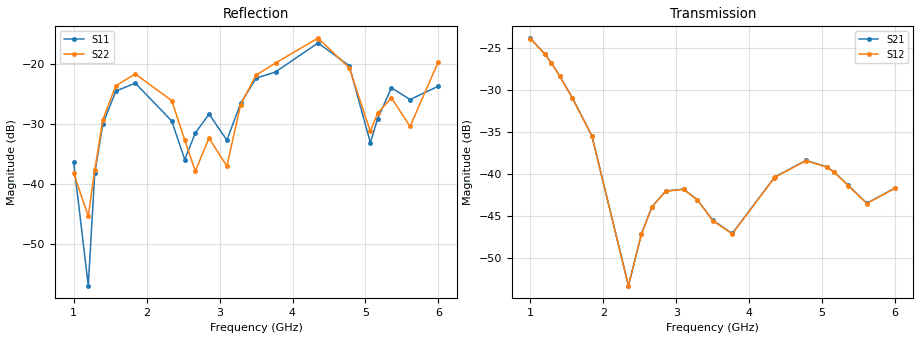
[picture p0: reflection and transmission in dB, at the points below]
!Agilent Technologies,E8364B,MY43040528,A.07.50.67
!Agilent E8364B: A.07.50.67
!Date: Sunday, March 01, 2026 16:25:24
!Correction: S11(Full 2 Port(1,2))
!S21(Full 2 Port(1,2))
!S12(Full 2 Port(1,2))
!S22(Full 2 Port(1,2))
!S2P File: Measurements: S11, S21, S12, S22:
# Hz S  dB  R 50
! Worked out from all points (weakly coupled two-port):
!   451 points, 1 GHz to 6 GHz, reference 50 ohm
!   highest |S21| = -23.84 dB at 1 GHz (marker M1); lowest = -53.3 dB at 2.344 GHz (marker M2)
!   lowest |S11| = -56.9 dB at 1.2 GHz (marker M3), VSWR 1.00, Z = 50 - j0.135 ohm
!   |S11| at or under -10 dB: start of sweep to end of sweep
!   |S22| runs from -45.5 to -15.6 dB; largest |S21 - S12| = 0.00028
!   S11 on the Smith chart (normalised r, x): 1 GHz: 1.03, +0.01; 4.356 GHz: 1.20, -0.26; 6 GHz: 0.97, -0.13
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1e9  -36.34 24.0  -23.84 153.1  -23.88 153.1  -38.19 -15.4
1.2e9  -56.87 -69.7  -25.70 38.8  -25.74 38.8  -45.28 77.3
1.288889e9  -38.14 -149.8  -26.76 -11.6  -26.79 -11.5  -37.62 117.9
1.4e9  -29.95 -177.1  -28.28 -73.5  -28.31 -73.4  -29.23 102.9
1.577778e9  -24.49 140.2  -30.95 -169.8  -30.98 -169.8  -23.59 57.6
1.844444e9  -23.16 87.5  -35.46 47.9  -35.49 48.0  -21.63 -7.6
2.344444e9  -29.46 26.8  -53.29 -150.0  -53.29 -150.1  -26.07 -107.4
2.522222e9  -35.88 46.6  -47.13 174.1  -47.18 174.3  -32.62 -134.1
2.666667e9  -31.49 76.9  -43.89 104.4  -43.91 104.4  -37.79 -93.9
2.855556e9  -28.30 54.5  -42.02 5.6  -42.05 5.7  -32.32 -97.6
3.1e9  -32.65 55.7  -41.79 -124.4  -41.83 -124.4  -36.97 -84.8
3.288889e9  -26.53 78.3  -43.05 137.5  -43.08 137.5  -26.74 -77.4
3.5e9  -22.34 50.8  -45.49 37.1  -45.54 37.2  -21.84 -120.5
3.766667e9  -21.30 26.0  -47.07 -65.9  -47.13 -65.7  -19.81 -161.5
4.344444e9  -16.52 -43.6  -40.42 22.8  -40.45 22.8  -15.71 100.2
4.355556e9  -16.52 -45.3  -40.32 16.8  -40.36 16.8  -15.74 97.9
4.777778e9  -20.26 -115.2  -38.37 140.2  -38.41 140.2  -20.62 14.4
5.066667e9  -33.06 -106.3  -39.14 -30.2  -39.18 -30.2  -31.19 23.0
5.166667e9  -29.09 -68.4  -39.77 -90.5  -39.81 -90.5  -28.15 37.2
5.355556e9  -23.93 -86.9  -41.32 151.7  -41.36 151.7  -25.60 11.4
5.611111e9  -25.89 -114.1  -43.47 -22.5  -43.51 -22.5  -30.37 12.4
6e9  -23.67 -100.7  -41.65 59.9  -41.68 60.0  -19.56 -16.8
